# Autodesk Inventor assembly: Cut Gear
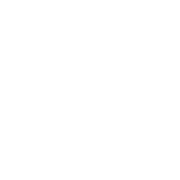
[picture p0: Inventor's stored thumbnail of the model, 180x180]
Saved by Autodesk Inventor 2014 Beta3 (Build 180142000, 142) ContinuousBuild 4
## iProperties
Created: 2011-01
Part Number: Cut Gear
Document SubType Name: Assembly
Designer: Beta-8540w
Categories: <?xml version="1.0" encoding="UTF-16"?> <MemberInstance><Categories><FamilyTemplate/><ParamToTemplateMap><ParamToTemplate><ParamToTemplate CategoryParameter="//
ClientObjectVersion: 1
Author: Beta-8540w
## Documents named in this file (1)
- C:\Inventor 2014 Essentials\Assemblies\Chapter 09\Design Accelerators\Cut Gear c09-01.iam
